VERSION 5.8 ;
BUSBITCHARS "[]" ;
DIVIDERCHAR "/" ;
UNITS
    DATABASE MICRONS 2000 ;
END UNITS

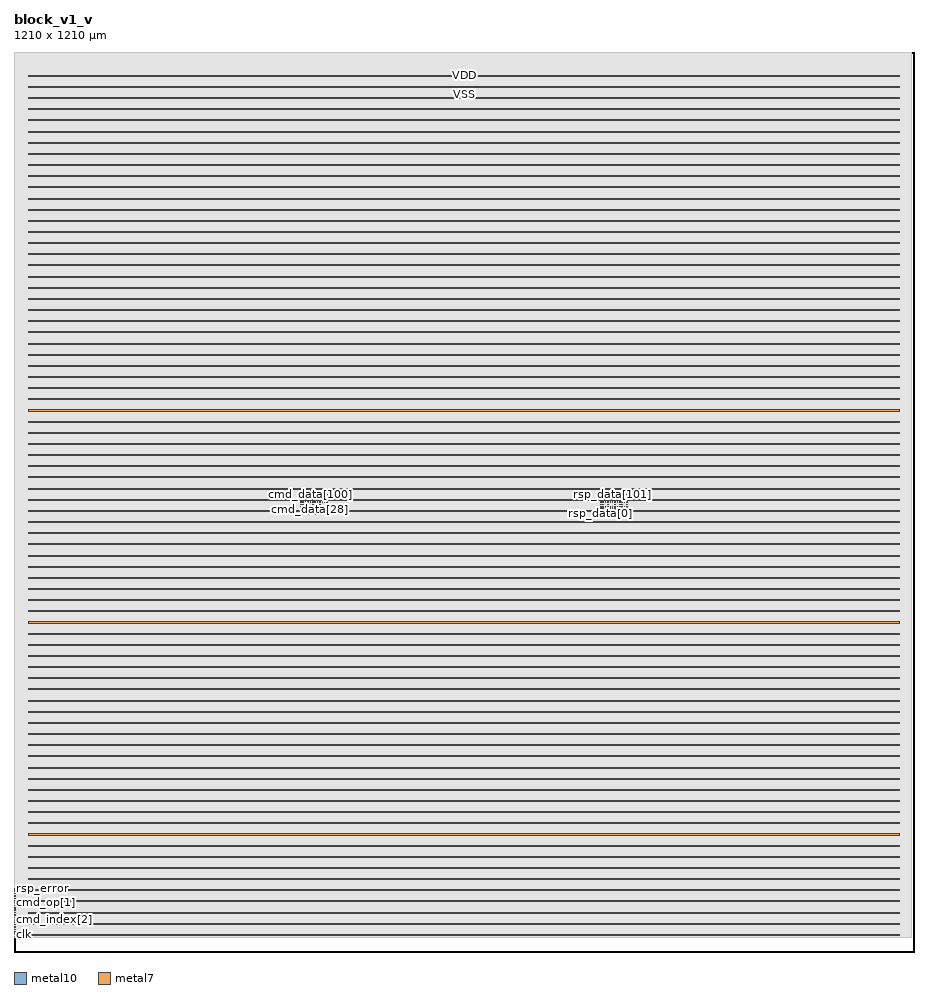
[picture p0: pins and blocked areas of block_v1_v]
MACRO block_v1_v
  FOREIGN block_v1_v 0 0 ;
  CLASS BLOCK ;
  SIZE 1210 BY 1210 ;
  PIN busy
    DIRECTION OUTPUT ;
    USE SIGNAL ;
    PORT
      LAYER metal10 ;
        RECT  1.295 20.47 2.095 21.27 ;
    END
  END busy
  PIN clk
    DIRECTION INPUT ;
    USE SIGNAL ;
    PORT
      LAYER metal10 ;
        RECT  1.295 23.67 2.095 24.47 ;
    END
  END clk
  PIN cmd_data[0]
    DIRECTION INPUT ;
    USE SIGNAL ;
    PORT
      LAYER metal10 ;
        RECT  385.295 588.47 386.095 589.27 ;
    END
  END cmd_data[0]
  PIN cmd_data[100]
    DIRECTION INPUT ;
    USE SIGNAL ;
    PORT
      LAYER metal10 ;
        RECT  398.095 614.07 398.895 614.87 ;
    END
  END cmd_data[100]
  PIN cmd_data[101]
    DIRECTION INPUT ;
    USE SIGNAL ;
    PORT
      LAYER metal10 ;
        RECT  401.295 614.07 402.095 614.87 ;
    END
  END cmd_data[101]
  PIN cmd_data[102]
    DIRECTION INPUT ;
    USE SIGNAL ;
    PORT
      LAYER metal10 ;
        RECT  404.495 614.07 405.295 614.87 ;
    END
  END cmd_data[102]
  PIN cmd_data[103]
    DIRECTION INPUT ;
    USE SIGNAL ;
    PORT
      LAYER metal10 ;
        RECT  407.695 614.07 408.495 614.87 ;
    END
  END cmd_data[103]
  PIN cmd_data[104]
    DIRECTION INPUT ;
    USE SIGNAL ;
    PORT
      LAYER metal10 ;
        RECT  410.895 614.07 411.695 614.87 ;
    END
  END cmd_data[104]
  PIN cmd_data[105]
    DIRECTION INPUT ;
    USE SIGNAL ;
    PORT
      LAYER metal10 ;
        RECT  414.095 614.07 414.895 614.87 ;
    END
  END cmd_data[105]
  PIN cmd_data[106]
    DIRECTION INPUT ;
    USE SIGNAL ;
    PORT
      LAYER metal10 ;
        RECT  417.295 614.07 418.095 614.87 ;
    END
  END cmd_data[106]
  PIN cmd_data[107]
    DIRECTION INPUT ;
    USE SIGNAL ;
    PORT
      LAYER metal10 ;
        RECT  420.495 614.07 421.295 614.87 ;
    END
  END cmd_data[107]
  PIN cmd_data[108]
    DIRECTION INPUT ;
    USE SIGNAL ;
    PORT
      LAYER metal10 ;
        RECT  385.295 617.27 386.095 618.07 ;
    END
  END cmd_data[108]
  PIN cmd_data[109]
    DIRECTION INPUT ;
    USE SIGNAL ;
    PORT
      LAYER metal10 ;
        RECT  388.495 617.27 389.295 618.07 ;
    END
  END cmd_data[109]
  PIN cmd_data[10]
    DIRECTION INPUT ;
    USE SIGNAL ;
    PORT
      LAYER metal10 ;
        RECT  417.295 588.47 418.095 589.27 ;
    END
  END cmd_data[10]
  PIN cmd_data[110]
    DIRECTION INPUT ;
    USE SIGNAL ;
    PORT
      LAYER metal10 ;
        RECT  391.695 617.27 392.495 618.07 ;
    END
  END cmd_data[110]
  PIN cmd_data[111]
    DIRECTION INPUT ;
    USE SIGNAL ;
    PORT
      LAYER metal10 ;
        RECT  394.895 617.27 395.695 618.07 ;
    END
  END cmd_data[111]
  PIN cmd_data[112]
    DIRECTION INPUT ;
    USE SIGNAL ;
    PORT
      LAYER metal10 ;
        RECT  398.095 617.27 398.895 618.07 ;
    END
  END cmd_data[112]
  PIN cmd_data[113]
    DIRECTION INPUT ;
    USE SIGNAL ;
    PORT
      LAYER metal10 ;
        RECT  401.295 617.27 402.095 618.07 ;
    END
  END cmd_data[113]
  PIN cmd_data[114]
    DIRECTION INPUT ;
    USE SIGNAL ;
    PORT
      LAYER metal10 ;
        RECT  404.495 617.27 405.295 618.07 ;
    END
  END cmd_data[114]
  PIN cmd_data[115]
    DIRECTION INPUT ;
    USE SIGNAL ;
    PORT
      LAYER metal10 ;
        RECT  407.695 617.27 408.495 618.07 ;
    END
  END cmd_data[115]
  PIN cmd_data[116]
    DIRECTION INPUT ;
    USE SIGNAL ;
    PORT
      LAYER metal10 ;
        RECT  410.895 617.27 411.695 618.07 ;
    END
  END cmd_data[116]
  PIN cmd_data[117]
    DIRECTION INPUT ;
    USE SIGNAL ;
    PORT
      LAYER metal10 ;
        RECT  414.095 617.27 414.895 618.07 ;
    END
  END cmd_data[117]
  PIN cmd_data[118]
    DIRECTION INPUT ;
    USE SIGNAL ;
    PORT
      LAYER metal10 ;
        RECT  417.295 617.27 418.095 618.07 ;
    END
  END cmd_data[118]
  PIN cmd_data[119]
    DIRECTION INPUT ;
    USE SIGNAL ;
    PORT
      LAYER metal10 ;
        RECT  420.495 617.27 421.295 618.07 ;
    END
  END cmd_data[119]
  PIN cmd_data[11]
    DIRECTION INPUT ;
    USE SIGNAL ;
    PORT
      LAYER metal10 ;
        RECT  420.495 588.47 421.295 589.27 ;
    END
  END cmd_data[11]
  PIN cmd_data[120]
    DIRECTION INPUT ;
    USE SIGNAL ;
    PORT
      LAYER metal10 ;
        RECT  385.295 620.47 386.095 621.27 ;
    END
  END cmd_data[120]
  PIN cmd_data[121]
    DIRECTION INPUT ;
    USE SIGNAL ;
    PORT
      LAYER metal10 ;
        RECT  388.495 620.47 389.295 621.27 ;
    END
  END cmd_data[121]
  PIN cmd_data[122]
    DIRECTION INPUT ;
    USE SIGNAL ;
    PORT
      LAYER metal10 ;
        RECT  391.695 620.47 392.495 621.27 ;
    END
  END cmd_data[122]
  PIN cmd_data[123]
    DIRECTION INPUT ;
    USE SIGNAL ;
    PORT
      LAYER metal10 ;
        RECT  394.895 620.47 395.695 621.27 ;
    END
  END cmd_data[123]
  PIN cmd_data[124]
    DIRECTION INPUT ;
    USE SIGNAL ;
    PORT
      LAYER metal10 ;
        RECT  398.095 620.47 398.895 621.27 ;
    END
  END cmd_data[124]
  PIN cmd_data[125]
    DIRECTION INPUT ;
    USE SIGNAL ;
    PORT
      LAYER metal10 ;
        RECT  401.295 620.47 402.095 621.27 ;
    END
  END cmd_data[125]
  PIN cmd_data[126]
    DIRECTION INPUT ;
    USE SIGNAL ;
    PORT
      LAYER metal10 ;
        RECT  404.495 620.47 405.295 621.27 ;
    END
  END cmd_data[126]
  PIN cmd_data[127]
    DIRECTION INPUT ;
    USE SIGNAL ;
    PORT
      LAYER metal10 ;
        RECT  407.695 620.47 408.495 621.27 ;
    END
  END cmd_data[127]
  PIN cmd_data[12]
    DIRECTION INPUT ;
    USE SIGNAL ;
    PORT
      LAYER metal10 ;
        RECT  385.295 591.67 386.095 592.47 ;
    END
  END cmd_data[12]
  PIN cmd_data[13]
    DIRECTION INPUT ;
    USE SIGNAL ;
    PORT
      LAYER metal10 ;
        RECT  388.495 591.67 389.295 592.47 ;
    END
  END cmd_data[13]
  PIN cmd_data[14]
    DIRECTION INPUT ;
    USE SIGNAL ;
    PORT
      LAYER metal10 ;
        RECT  391.695 591.67 392.495 592.47 ;
    END
  END cmd_data[14]
  PIN cmd_data[15]
    DIRECTION INPUT ;
    USE SIGNAL ;
    PORT
      LAYER metal10 ;
        RECT  394.895 591.67 395.695 592.47 ;
    END
  END cmd_data[15]
  PIN cmd_data[16]
    DIRECTION INPUT ;
    USE SIGNAL ;
    PORT
      LAYER metal10 ;
        RECT  398.095 591.67 398.895 592.47 ;
    END
  END cmd_data[16]
  PIN cmd_data[17]
    DIRECTION INPUT ;
    USE SIGNAL ;
    PORT
      LAYER metal10 ;
        RECT  401.295 591.67 402.095 592.47 ;
    END
  END cmd_data[17]
  PIN cmd_data[18]
    DIRECTION INPUT ;
    USE SIGNAL ;
    PORT
      LAYER metal10 ;
        RECT  404.495 591.67 405.295 592.47 ;
    END
  END cmd_data[18]
  PIN cmd_data[19]
    DIRECTION INPUT ;
    USE SIGNAL ;
    PORT
      LAYER metal10 ;
        RECT  407.695 591.67 408.495 592.47 ;
    END
  END cmd_data[19]
  PIN cmd_data[1]
    DIRECTION INPUT ;
    USE SIGNAL ;
    PORT
      LAYER metal10 ;
        RECT  388.495 588.47 389.295 589.27 ;
    END
  END cmd_data[1]
  PIN cmd_data[20]
    DIRECTION INPUT ;
    USE SIGNAL ;
    PORT
      LAYER metal10 ;
        RECT  410.895 591.67 411.695 592.47 ;
    END
  END cmd_data[20]
  PIN cmd_data[21]
    DIRECTION INPUT ;
    USE SIGNAL ;
    PORT
      LAYER metal10 ;
        RECT  414.095 591.67 414.895 592.47 ;
    END
  END cmd_data[21]
  PIN cmd_data[22]
    DIRECTION INPUT ;
    USE SIGNAL ;
    PORT
      LAYER metal10 ;
        RECT  417.295 591.67 418.095 592.47 ;
    END
  END cmd_data[22]
  PIN cmd_data[23]
    DIRECTION INPUT ;
    USE SIGNAL ;
    PORT
      LAYER metal10 ;
        RECT  420.495 591.67 421.295 592.47 ;
    END
  END cmd_data[23]
  PIN cmd_data[24]
    DIRECTION INPUT ;
    USE SIGNAL ;
    PORT
      LAYER metal10 ;
        RECT  385.295 594.87 386.095 595.67 ;
    END
  END cmd_data[24]
  PIN cmd_data[25]
    DIRECTION INPUT ;
    USE SIGNAL ;
    PORT
      LAYER metal10 ;
        RECT  388.495 594.87 389.295 595.67 ;
    END
  END cmd_data[25]
  PIN cmd_data[26]
    DIRECTION INPUT ;
    USE SIGNAL ;
    PORT
      LAYER metal10 ;
        RECT  391.695 594.87 392.495 595.67 ;
    END
  END cmd_data[26]
  PIN cmd_data[27]
    DIRECTION INPUT ;
    USE SIGNAL ;
    PORT
      LAYER metal10 ;
        RECT  394.895 594.87 395.695 595.67 ;
    END
  END cmd_data[27]
  PIN cmd_data[28]
    DIRECTION INPUT ;
    USE SIGNAL ;
    PORT
      LAYER metal10 ;
        RECT  398.095 594.87 398.895 595.67 ;
    END
  END cmd_data[28]
  PIN cmd_data[29]
    DIRECTION INPUT ;
    USE SIGNAL ;
    PORT
      LAYER metal10 ;
        RECT  401.295 594.87 402.095 595.67 ;
    END
  END cmd_data[29]
  PIN cmd_data[2]
    DIRECTION INPUT ;
    USE SIGNAL ;
    PORT
      LAYER metal10 ;
        RECT  391.695 588.47 392.495 589.27 ;
    END
  END cmd_data[2]
  PIN cmd_data[30]
    DIRECTION INPUT ;
    USE SIGNAL ;
    PORT
      LAYER metal10 ;
        RECT  404.495 594.87 405.295 595.67 ;
    END
  END cmd_data[30]
  PIN cmd_data[31]
    DIRECTION INPUT ;
    USE SIGNAL ;
    PORT
      LAYER metal10 ;
        RECT  407.695 594.87 408.495 595.67 ;
    END
  END cmd_data[31]
  PIN cmd_data[32]
    DIRECTION INPUT ;
    USE SIGNAL ;
    PORT
      LAYER metal10 ;
        RECT  410.895 594.87 411.695 595.67 ;
    END
  END cmd_data[32]
  PIN cmd_data[33]
    DIRECTION INPUT ;
    USE SIGNAL ;
    PORT
      LAYER metal10 ;
        RECT  414.095 594.87 414.895 595.67 ;
    END
  END cmd_data[33]
  PIN cmd_data[34]
    DIRECTION INPUT ;
    USE SIGNAL ;
    PORT
      LAYER metal10 ;
        RECT  417.295 594.87 418.095 595.67 ;
    END
  END cmd_data[34]
  PIN cmd_data[35]
    DIRECTION INPUT ;
    USE SIGNAL ;
    PORT
      LAYER metal10 ;
        RECT  420.495 594.87 421.295 595.67 ;
    END
  END cmd_data[35]
  PIN cmd_data[36]
    DIRECTION INPUT ;
    USE SIGNAL ;
    PORT
      LAYER metal10 ;
        RECT  385.295 598.07 386.095 598.87 ;
    END
  END cmd_data[36]
  PIN cmd_data[37]
    DIRECTION INPUT ;
    USE SIGNAL ;
    PORT
      LAYER metal10 ;
        RECT  388.495 598.07 389.295 598.87 ;
    END
  END cmd_data[37]
  PIN cmd_data[38]
    DIRECTION INPUT ;
    USE SIGNAL ;
    PORT
      LAYER metal10 ;
        RECT  391.695 598.07 392.495 598.87 ;
    END
  END cmd_data[38]
  PIN cmd_data[39]
    DIRECTION INPUT ;
    USE SIGNAL ;
    PORT
      LAYER metal10 ;
        RECT  394.895 598.07 395.695 598.87 ;
    END
  END cmd_data[39]
  PIN cmd_data[3]
    DIRECTION INPUT ;
    USE SIGNAL ;
    PORT
      LAYER metal10 ;
        RECT  394.895 588.47 395.695 589.27 ;
    END
  END cmd_data[3]
  PIN cmd_data[40]
    DIRECTION INPUT ;
    USE SIGNAL ;
    PORT
      LAYER metal10 ;
        RECT  398.095 598.07 398.895 598.87 ;
    END
  END cmd_data[40]
  PIN cmd_data[41]
    DIRECTION INPUT ;
    USE SIGNAL ;
    PORT
      LAYER metal10 ;
        RECT  401.295 598.07 402.095 598.87 ;
    END
  END cmd_data[41]
  PIN cmd_data[42]
    DIRECTION INPUT ;
    USE SIGNAL ;
    PORT
      LAYER metal10 ;
        RECT  404.495 598.07 405.295 598.87 ;
    END
  END cmd_data[42]
  PIN cmd_data[43]
    DIRECTION INPUT ;
    USE SIGNAL ;
    PORT
      LAYER metal10 ;
        RECT  407.695 598.07 408.495 598.87 ;
    END
  END cmd_data[43]
  PIN cmd_data[44]
    DIRECTION INPUT ;
    USE SIGNAL ;
    PORT
      LAYER metal10 ;
        RECT  410.895 598.07 411.695 598.87 ;
    END
  END cmd_data[44]
  PIN cmd_data[45]
    DIRECTION INPUT ;
    USE SIGNAL ;
    PORT
      LAYER metal10 ;
        RECT  414.095 598.07 414.895 598.87 ;
    END
  END cmd_data[45]
  PIN cmd_data[46]
    DIRECTION INPUT ;
    USE SIGNAL ;
    PORT
      LAYER metal10 ;
        RECT  417.295 598.07 418.095 598.87 ;
    END
  END cmd_data[46]
  PIN cmd_data[47]
    DIRECTION INPUT ;
    USE SIGNAL ;
    PORT
      LAYER metal10 ;
        RECT  420.495 598.07 421.295 598.87 ;
    END
  END cmd_data[47]
  PIN cmd_data[48]
    DIRECTION INPUT ;
    USE SIGNAL ;
    PORT
      LAYER metal10 ;
        RECT  385.295 601.27 386.095 602.07 ;
    END
  END cmd_data[48]
  PIN cmd_data[49]
    DIRECTION INPUT ;
    USE SIGNAL ;
    PORT
      LAYER metal10 ;
        RECT  388.495 601.27 389.295 602.07 ;
    END
  END cmd_data[49]
  PIN cmd_data[4]
    DIRECTION INPUT ;
    USE SIGNAL ;
    PORT
      LAYER metal10 ;
        RECT  398.095 588.47 398.895 589.27 ;
    END
  END cmd_data[4]
  PIN cmd_data[50]
    DIRECTION INPUT ;
    USE SIGNAL ;
    PORT
      LAYER metal10 ;
        RECT  391.695 601.27 392.495 602.07 ;
    END
  END cmd_data[50]
  PIN cmd_data[51]
    DIRECTION INPUT ;
    USE SIGNAL ;
    PORT
      LAYER metal10 ;
        RECT  394.895 601.27 395.695 602.07 ;
    END
  END cmd_data[51]
  PIN cmd_data[52]
    DIRECTION INPUT ;
    USE SIGNAL ;
    PORT
      LAYER metal10 ;
        RECT  398.095 601.27 398.895 602.07 ;
    END
  END cmd_data[52]
  PIN cmd_data[53]
    DIRECTION INPUT ;
    USE SIGNAL ;
    PORT
      LAYER metal10 ;
        RECT  401.295 601.27 402.095 602.07 ;
    END
  END cmd_data[53]
  PIN cmd_data[54]
    DIRECTION INPUT ;
    USE SIGNAL ;
    PORT
      LAYER metal10 ;
        RECT  404.495 601.27 405.295 602.07 ;
    END
  END cmd_data[54]
  PIN cmd_data[55]
    DIRECTION INPUT ;
    USE SIGNAL ;
    PORT
      LAYER metal10 ;
        RECT  407.695 601.27 408.495 602.07 ;
    END
  END cmd_data[55]
  PIN cmd_data[56]
    DIRECTION INPUT ;
    USE SIGNAL ;
    PORT
      LAYER metal10 ;
        RECT  410.895 601.27 411.695 602.07 ;
    END
  END cmd_data[56]
  PIN cmd_data[57]
    DIRECTION INPUT ;
    USE SIGNAL ;
    PORT
      LAYER metal10 ;
        RECT  414.095 601.27 414.895 602.07 ;
    END
  END cmd_data[57]
  PIN cmd_data[58]
    DIRECTION INPUT ;
    USE SIGNAL ;
    PORT
      LAYER metal10 ;
        RECT  417.295 601.27 418.095 602.07 ;
    END
  END cmd_data[58]
  PIN cmd_data[59]
    DIRECTION INPUT ;
    USE SIGNAL ;
    PORT
      LAYER metal10 ;
        RECT  420.495 601.27 421.295 602.07 ;
    END
  END cmd_data[59]
  PIN cmd_data[5]
    DIRECTION INPUT ;
    USE SIGNAL ;
    PORT
      LAYER metal10 ;
        RECT  401.295 588.47 402.095 589.27 ;
    END
  END cmd_data[5]
  PIN cmd_data[60]
    DIRECTION INPUT ;
    USE SIGNAL ;
    PORT
      LAYER metal10 ;
        RECT  385.295 604.47 386.095 605.27 ;
    END
  END cmd_data[60]
  PIN cmd_data[61]
    DIRECTION INPUT ;
    USE SIGNAL ;
    PORT
      LAYER metal10 ;
        RECT  388.495 604.47 389.295 605.27 ;
    END
  END cmd_data[61]
  PIN cmd_data[62]
    DIRECTION INPUT ;
    USE SIGNAL ;
    PORT
      LAYER metal10 ;
        RECT  391.695 604.47 392.495 605.27 ;
    END
  END cmd_data[62]
  PIN cmd_data[63]
    DIRECTION INPUT ;
    USE SIGNAL ;
    PORT
      LAYER metal10 ;
        RECT  394.895 604.47 395.695 605.27 ;
    END
  END cmd_data[63]
  PIN cmd_data[64]
    DIRECTION INPUT ;
    USE SIGNAL ;
    PORT
      LAYER metal10 ;
        RECT  398.095 604.47 398.895 605.27 ;
    END
  END cmd_data[64]
  PIN cmd_data[65]
    DIRECTION INPUT ;
    USE SIGNAL ;
    PORT
      LAYER metal10 ;
        RECT  401.295 604.47 402.095 605.27 ;
    END
  END cmd_data[65]
  PIN cmd_data[66]
    DIRECTION INPUT ;
    USE SIGNAL ;
    PORT
      LAYER metal10 ;
        RECT  404.495 604.47 405.295 605.27 ;
    END
  END cmd_data[66]
  PIN cmd_data[67]
    DIRECTION INPUT ;
    USE SIGNAL ;
    PORT
      LAYER metal10 ;
        RECT  407.695 604.47 408.495 605.27 ;
    END
  END cmd_data[67]
  PIN cmd_data[68]
    DIRECTION INPUT ;
    USE SIGNAL ;
    PORT
      LAYER metal10 ;
        RECT  410.895 604.47 411.695 605.27 ;
    END
  END cmd_data[68]
  PIN cmd_data[69]
    DIRECTION INPUT ;
    USE SIGNAL ;
    PORT
      LAYER metal10 ;
        RECT  414.095 604.47 414.895 605.27 ;
    END
  END cmd_data[69]
  PIN cmd_data[6]
    DIRECTION INPUT ;
    USE SIGNAL ;
    PORT
      LAYER metal10 ;
        RECT  404.495 588.47 405.295 589.27 ;
    END
  END cmd_data[6]
  PIN cmd_data[70]
    DIRECTION INPUT ;
    USE SIGNAL ;
    PORT
      LAYER metal10 ;
        RECT  417.295 604.47 418.095 605.27 ;
    END
  END cmd_data[70]
  PIN cmd_data[71]
    DIRECTION INPUT ;
    USE SIGNAL ;
    PORT
      LAYER metal10 ;
        RECT  420.495 604.47 421.295 605.27 ;
    END
  END cmd_data[71]
  PIN cmd_data[72]
    DIRECTION INPUT ;
    USE SIGNAL ;
    PORT
      LAYER metal10 ;
        RECT  385.295 607.67 386.095 608.47 ;
    END
  END cmd_data[72]
  PIN cmd_data[73]
    DIRECTION INPUT ;
    USE SIGNAL ;
    PORT
      LAYER metal10 ;
        RECT  388.495 607.67 389.295 608.47 ;
    END
  END cmd_data[73]
  PIN cmd_data[74]
    DIRECTION INPUT ;
    USE SIGNAL ;
    PORT
      LAYER metal10 ;
        RECT  391.695 607.67 392.495 608.47 ;
    END
  END cmd_data[74]
  PIN cmd_data[75]
    DIRECTION INPUT ;
    USE SIGNAL ;
    PORT
      LAYER metal10 ;
        RECT  394.895 607.67 395.695 608.47 ;
    END
  END cmd_data[75]
  PIN cmd_data[76]
    DIRECTION INPUT ;
    USE SIGNAL ;
    PORT
      LAYER metal10 ;
        RECT  398.095 607.67 398.895 608.47 ;
    END
  END cmd_data[76]
  PIN cmd_data[77]
    DIRECTION INPUT ;
    USE SIGNAL ;
    PORT
      LAYER metal10 ;
        RECT  401.295 607.67 402.095 608.47 ;
    END
  END cmd_data[77]
  PIN cmd_data[78]
    DIRECTION INPUT ;
    USE SIGNAL ;
    PORT
      LAYER metal10 ;
        RECT  404.495 607.67 405.295 608.47 ;
    END
  END cmd_data[78]
  PIN cmd_data[79]
    DIRECTION INPUT ;
    USE SIGNAL ;
    PORT
      LAYER metal10 ;
        RECT  407.695 607.67 408.495 608.47 ;
    END
  END cmd_data[79]
  PIN cmd_data[7]
    DIRECTION INPUT ;
    USE SIGNAL ;
    PORT
      LAYER metal10 ;
        RECT  407.695 588.47 408.495 589.27 ;
    END
  END cmd_data[7]
  PIN cmd_data[80]
    DIRECTION INPUT ;
    USE SIGNAL ;
    PORT
      LAYER metal10 ;
        RECT  410.895 607.67 411.695 608.47 ;
    END
  END cmd_data[80]
  PIN cmd_data[81]
    DIRECTION INPUT ;
    USE SIGNAL ;
    PORT
      LAYER metal10 ;
        RECT  414.095 607.67 414.895 608.47 ;
    END
  END cmd_data[81]
  PIN cmd_data[82]
    DIRECTION INPUT ;
    USE SIGNAL ;
    PORT
      LAYER metal10 ;
        RECT  417.295 607.67 418.095 608.47 ;
    END
  END cmd_data[82]
  PIN cmd_data[83]
    DIRECTION INPUT ;
    USE SIGNAL ;
    PORT
      LAYER metal10 ;
        RECT  420.495 607.67 421.295 608.47 ;
    END
  END cmd_data[83]
  PIN cmd_data[84]
    DIRECTION INPUT ;
    USE SIGNAL ;
    PORT
      LAYER metal10 ;
        RECT  385.295 610.87 386.095 611.67 ;
    END
  END cmd_data[84]
  PIN cmd_data[85]
    DIRECTION INPUT ;
    USE SIGNAL ;
    PORT
      LAYER metal10 ;
        RECT  388.495 610.87 389.295 611.67 ;
    END
  END cmd_data[85]
  PIN cmd_data[86]
    DIRECTION INPUT ;
    USE SIGNAL ;
    PORT
      LAYER metal10 ;
        RECT  391.695 610.87 392.495 611.67 ;
    END
  END cmd_data[86]
  PIN cmd_data[87]
    DIRECTION INPUT ;
    USE SIGNAL ;
    PORT
      LAYER metal10 ;
        RECT  394.895 610.87 395.695 611.67 ;
    END
  END cmd_data[87]
  PIN cmd_data[88]
    DIRECTION INPUT ;
    USE SIGNAL ;
    PORT
      LAYER metal10 ;
        RECT  398.095 610.87 398.895 611.67 ;
    END
  END cmd_data[88]
  PIN cmd_data[89]
    DIRECTION INPUT ;
    USE SIGNAL ;
    PORT
      LAYER metal10 ;
        RECT  401.295 610.87 402.095 611.67 ;
    END
  END cmd_data[89]
  PIN cmd_data[8]
    DIRECTION INPUT ;
    USE SIGNAL ;
    PORT
      LAYER metal10 ;
        RECT  410.895 588.47 411.695 589.27 ;
    END
  END cmd_data[8]
  PIN cmd_data[90]
    DIRECTION INPUT ;
    USE SIGNAL ;
    PORT
      LAYER metal10 ;
        RECT  404.495 610.87 405.295 611.67 ;
    END
  END cmd_data[90]
  PIN cmd_data[91]
    DIRECTION INPUT ;
    USE SIGNAL ;
    PORT
      LAYER metal10 ;
        RECT  407.695 610.87 408.495 611.67 ;
    END
  END cmd_data[91]
  PIN cmd_data[92]
    DIRECTION INPUT ;
    USE SIGNAL ;
    PORT
      LAYER metal10 ;
        RECT  410.895 610.87 411.695 611.67 ;
    END
  END cmd_data[92]
  PIN cmd_data[93]
    DIRECTION INPUT ;
    USE SIGNAL ;
    PORT
      LAYER metal10 ;
        RECT  414.095 610.87 414.895 611.67 ;
    END
  END cmd_data[93]
  PIN cmd_data[94]
    DIRECTION INPUT ;
    USE SIGNAL ;
    PORT
      LAYER metal10 ;
        RECT  417.295 610.87 418.095 611.67 ;
    END
  END cmd_data[94]
  PIN cmd_data[95]
    DIRECTION INPUT ;
    USE SIGNAL ;
    PORT
      LAYER metal10 ;
        RECT  420.495 610.87 421.295 611.67 ;
    END
  END cmd_data[95]
  PIN cmd_data[96]
    DIRECTION INPUT ;
    USE SIGNAL ;
    PORT
      LAYER metal10 ;
        RECT  385.295 614.07 386.095 614.87 ;
    END
  END cmd_data[96]
  PIN cmd_data[97]
    DIRECTION INPUT ;
    USE SIGNAL ;
    PORT
      LAYER metal10 ;
        RECT  388.495 614.07 389.295 614.87 ;
    END
  END cmd_data[97]
  PIN cmd_data[98]
    DIRECTION INPUT ;
    USE SIGNAL ;
    PORT
      LAYER metal10 ;
        RECT  391.695 614.07 392.495 614.87 ;
    END
  END cmd_data[98]
  PIN cmd_data[99]
    DIRECTION INPUT ;
    USE SIGNAL ;
    PORT
      LAYER metal10 ;
        RECT  394.895 614.07 395.695 614.87 ;
    END
  END cmd_data[99]
  PIN cmd_data[9]
    DIRECTION INPUT ;
    USE SIGNAL ;
    PORT
      LAYER metal10 ;
        RECT  414.095 588.47 414.895 589.27 ;
    END
  END cmd_data[9]
  PIN cmd_index[0]
    DIRECTION INPUT ;
    USE SIGNAL ;
    PORT
      LAYER metal10 ;
        RECT  1.295 26.87 2.095 27.67 ;
    END
  END cmd_index[0]
  PIN cmd_index[1]
    DIRECTION INPUT ;
    USE SIGNAL ;
    PORT
      LAYER metal10 ;
        RECT  1.295 30.07 2.095 30.87 ;
    END
  END cmd_index[1]
  PIN cmd_index[2]
    DIRECTION INPUT ;
    USE SIGNAL ;
    PORT
      LAYER metal10 ;
        RECT  1.295 33.27 2.095 34.07 ;
    END
  END cmd_index[2]
  PIN cmd_index[3]
    DIRECTION INPUT ;
    USE SIGNAL ;
    PORT
      LAYER metal10 ;
        RECT  1.295 36.47 2.095 37.27 ;
    END
  END cmd_index[3]
  PIN cmd_index[4]
    DIRECTION INPUT ;
    USE SIGNAL ;
    PORT
      LAYER metal10 ;
        RECT  1.295 39.67 2.095 40.47 ;
    END
  END cmd_index[4]
  PIN cmd_index[5]
    DIRECTION INPUT ;
    USE SIGNAL ;
    PORT
      LAYER metal10 ;
        RECT  1.295 42.87 2.095 43.67 ;
    END
  END cmd_index[5]
  PIN cmd_index[6]
    DIRECTION INPUT ;
    USE SIGNAL ;
    PORT
      LAYER metal10 ;
        RECT  1.295 46.07 2.095 46.87 ;
    END
  END cmd_index[6]
  PIN cmd_index[7]
    DIRECTION INPUT ;
    USE SIGNAL ;
    PORT
      LAYER metal10 ;
        RECT  1.295 49.27 2.095 50.07 ;
    END
  END cmd_index[7]
  PIN cmd_op[0]
    DIRECTION INPUT ;
    USE SIGNAL ;
    PORT
      LAYER metal10 ;
        RECT  1.295 52.47 2.095 53.27 ;
    END
  END cmd_op[0]
  PIN cmd_op[1]
    DIRECTION INPUT ;
    USE SIGNAL ;
    PORT
      LAYER metal10 ;
        RECT  1.295 55.67 2.095 56.47 ;
    END
  END cmd_op[1]
  PIN cmd_op[2]
    DIRECTION INPUT ;
    USE SIGNAL ;
    PORT
      LAYER metal10 ;
        RECT  1.295 58.87 2.095 59.67 ;
    END
  END cmd_op[2]
  PIN cmd_op[3]
    DIRECTION INPUT ;
    USE SIGNAL ;
    PORT
      LAYER metal10 ;
        RECT  1.295 62.07 2.095 62.87 ;
    END
  END cmd_op[3]
  PIN cmd_ready
    DIRECTION OUTPUT ;
    USE SIGNAL ;
    PORT
      LAYER metal10 ;
        RECT  1.295 65.27 2.095 66.07 ;
    END
  END cmd_ready
  PIN cmd_valid
    DIRECTION INPUT ;
    USE SIGNAL ;
    PORT
      LAYER metal10 ;
        RECT  1.295 68.47 2.095 69.27 ;
    END
  END cmd_valid
  PIN reset
    DIRECTION INPUT ;
    USE SIGNAL ;
    PORT
      LAYER metal10 ;
        RECT  1.295 71.67 2.095 72.47 ;
    END
  END reset
  PIN rsp_data[0]
    DIRECTION OUTPUT ;
    USE SIGNAL ;
    PORT
      LAYER metal10 ;
        RECT  788.495 588.47 789.295 589.27 ;
    END
  END rsp_data[0]
  PIN rsp_data[100]
    DIRECTION OUTPUT ;
    USE SIGNAL ;
    PORT
      LAYER metal10 ;
        RECT  801.295 614.07 802.095 614.87 ;
    END
  END rsp_data[100]
  PIN rsp_data[101]
    DIRECTION OUTPUT ;
    USE SIGNAL ;
    PORT
      LAYER metal10 ;
        RECT  804.495 614.07 805.295 614.87 ;
    END
  END rsp_data[101]
  PIN rsp_data[102]
    DIRECTION OUTPUT ;
    USE SIGNAL ;
    PORT
      LAYER metal10 ;
        RECT  807.695 614.07 808.495 614.87 ;
    END
  END rsp_data[102]
  PIN rsp_data[103]
    DIRECTION OUTPUT ;
    USE SIGNAL ;
    PORT
      LAYER metal10 ;
        RECT  810.895 614.07 811.695 614.87 ;
    END
  END rsp_data[103]
  PIN rsp_data[104]
    DIRECTION OUTPUT ;
    USE SIGNAL ;
    PORT
      LAYER metal10 ;
        RECT  814.095 614.07 814.895 614.87 ;
    END
  END rsp_data[104]
  PIN rsp_data[105]
    DIRECTION OUTPUT ;
    USE SIGNAL ;
    PORT
      LAYER metal10 ;
        RECT  817.295 614.07 818.095 614.87 ;
    END
  END rsp_data[105]
  PIN rsp_data[106]
    DIRECTION OUTPUT ;
    USE SIGNAL ;
    PORT
      LAYER metal10 ;
        RECT  820.495 614.07 821.295 614.87 ;
    END
  END rsp_data[106]
  PIN rsp_data[107]
    DIRECTION OUTPUT ;
    USE SIGNAL ;
    PORT
      LAYER metal10 ;
        RECT  823.695 614.07 824.495 614.87 ;
    END
  END rsp_data[107]
  PIN rsp_data[108]
    DIRECTION OUTPUT ;
    USE SIGNAL ;
    PORT
      LAYER metal10 ;
        RECT  788.495 617.27 789.295 618.07 ;
    END
  END rsp_data[108]
  PIN rsp_data[109]
    DIRECTION OUTPUT ;
    USE SIGNAL ;
    PORT
      LAYER metal10 ;
        RECT  791.695 617.27 792.495 618.07 ;
    END
  END rsp_data[109]
  PIN rsp_data[10]
    DIRECTION OUTPUT ;
    USE SIGNAL ;
    PORT
      LAYER metal10 ;
        RECT  820.495 588.47 821.295 589.27 ;
    END
  END rsp_data[10]
  PIN rsp_data[110]
    DIRECTION OUTPUT ;
    USE SIGNAL ;
    PORT
      LAYER metal10 ;
        RECT  794.895 617.27 795.695 618.07 ;
    END
  END rsp_data[110]
  PIN rsp_data[111]
    DIRECTION OUTPUT ;
    USE SIGNAL ;
    PORT
      LAYER metal10 ;
        RECT  798.095 617.27 798.895 618.07 ;
    END
  END rsp_data[111]
  PIN rsp_data[112]
    DIRECTION OUTPUT ;
    USE SIGNAL ;
    PORT
      LAYER metal10 ;
        RECT  801.295 617.27 802.095 618.07 ;
    END
  END rsp_data[112]
  PIN rsp_data[113]
    DIRECTION OUTPUT ;
    USE SIGNAL ;
    PORT
      LAYER metal10 ;
        RECT  804.495 617.27 805.295 618.07 ;
    END
  END rsp_data[113]
  PIN rsp_data[114]
    DIRECTION OUTPUT ;
    USE SIGNAL ;
    PORT
      LAYER metal10 ;
        RECT  807.695 617.27 808.495 618.07 ;
    END
  END rsp_data[114]
  PIN rsp_data[115]
    DIRECTION OUTPUT ;
    USE SIGNAL ;
    PORT
      LAYER metal10 ;
        RECT  810.895 617.27 811.695 618.07 ;
    END
  END rsp_data[115]
  PIN rsp_data[116]
    DIRECTION OUTPUT ;
    USE SIGNAL ;
    PORT
      LAYER metal10 ;
        RECT  814.095 617.27 814.895 618.07 ;
    END
  END rsp_data[116]
  PIN rsp_data[117]
    DIRECTION OUTPUT ;
    USE SIGNAL ;
    PORT
      LAYER metal10 ;
        RECT  817.295 617.27 818.095 618.07 ;
    END
  END rsp_data[117]
  PIN rsp_data[118]
    DIRECTION OUTPUT ;
    USE SIGNAL ;
    PORT
      LAYER metal10 ;
        RECT  820.495 617.27 821.295 618.07 ;
    END
  END rsp_data[118]
  PIN rsp_data[119]
    DIRECTION OUTPUT ;
    USE SIGNAL ;
    PORT
      LAYER metal10 ;
        RECT  823.695 617.27 824.495 618.07 ;
    END
  END rsp_data[119]
  PIN rsp_data[11]
    DIRECTION OUTPUT ;
    USE SIGNAL ;
    PORT
      LAYER metal10 ;
        RECT  823.695 588.47 824.495 589.27 ;
    END
  END rsp_data[11]
  PIN rsp_data[120]
    DIRECTION OUTPUT ;
    USE SIGNAL ;
    PORT
      LAYER metal10 ;
        RECT  788.495 620.47 789.295 621.27 ;
    END
  END rsp_data[120]
  PIN rsp_data[121]
    DIRECTION OUTPUT ;
    USE SIGNAL ;
    PORT
      LAYER metal10 ;
        RECT  791.695 620.47 792.495 621.27 ;
    END
  END rsp_data[121]
  PIN rsp_data[122]
    DIRECTION OUTPUT ;
    USE SIGNAL ;
    PORT
      LAYER metal10 ;
        RECT  794.895 620.47 795.695 621.27 ;
    END
  END rsp_data[122]
  PIN rsp_data[123]
    DIRECTION OUTPUT ;
    USE SIGNAL ;
    PORT
      LAYER metal10 ;
        RECT  798.095 620.47 798.895 621.27 ;
    END
  END rsp_data[123]
  PIN rsp_data[124]
    DIRECTION OUTPUT ;
    USE SIGNAL ;
    PORT
      LAYER metal10 ;
        RECT  801.295 620.47 802.095 621.27 ;
    END
  END rsp_data[124]
  PIN rsp_data[125]
    DIRECTION OUTPUT ;
    USE SIGNAL ;
    PORT
      LAYER metal10 ;
        RECT  804.495 620.47 805.295 621.27 ;
    END
  END rsp_data[125]
  PIN rsp_data[126]
    DIRECTION OUTPUT ;
    USE SIGNAL ;
    PORT
      LAYER metal10 ;
        RECT  807.695 620.47 808.495 621.27 ;
    END
  END rsp_data[126]
  PIN rsp_data[127]
    DIRECTION OUTPUT ;
    USE SIGNAL ;
    PORT
      LAYER metal10 ;
        RECT  810.895 620.47 811.695 621.27 ;
    END
  END rsp_data[127]
  PIN rsp_data[12]
    DIRECTION OUTPUT ;
    USE SIGNAL ;
    PORT
      LAYER metal10 ;
        RECT  788.495 591.67 789.295 592.47 ;
    END
  END rsp_data[12]
  PIN rsp_data[13]
    DIRECTION OUTPUT ;
    USE SIGNAL ;
    PORT
      LAYER metal10 ;
        RECT  791.695 591.67 792.495 592.47 ;
    END
  END rsp_data[13]
  PIN rsp_data[14]
    DIRECTION OUTPUT ;
    USE SIGNAL ;
    PORT
      LAYER metal10 ;
        RECT  794.895 591.67 795.695 592.47 ;
    END
  END rsp_data[14]
  PIN rsp_data[15]
    DIRECTION OUTPUT ;
    USE SIGNAL ;
    PORT
      LAYER metal10 ;
        RECT  798.095 591.67 798.895 592.47 ;
    END
  END rsp_data[15]
  PIN rsp_data[16]
    DIRECTION OUTPUT ;
    USE SIGNAL ;
    PORT
      LAYER metal10 ;
        RECT  801.295 591.67 802.095 592.47 ;
    END
  END rsp_data[16]
  PIN rsp_data[17]
    DIRECTION OUTPUT ;
    USE SIGNAL ;
    PORT
      LAYER metal10 ;
        RECT  804.495 591.67 805.295 592.47 ;
    END
  END rsp_data[17]
  PIN rsp_data[18]
    DIRECTION OUTPUT ;
    USE SIGNAL ;
    PORT
      LAYER metal10 ;
        RECT  807.695 591.67 808.495 592.47 ;
    END
  END rsp_data[18]
  PIN rsp_data[19]
    DIRECTION OUTPUT ;
    USE SIGNAL ;
    PORT
      LAYER metal10 ;
        RECT  810.895 591.67 811.695 592.47 ;
    END
  END rsp_data[19]
  PIN rsp_data[1]
    DIRECTION OUTPUT ;
    USE SIGNAL ;
    PORT
      LAYER metal10 ;
        RECT  791.695 588.47 792.495 589.27 ;
    END
  END rsp_data[1]
  PIN rsp_data[20]
    DIRECTION OUTPUT ;
    USE SIGNAL ;
    PORT
      LAYER metal10 ;
        RECT  814.095 591.67 814.895 592.47 ;
    END
  END rsp_data[20]
  PIN rsp_data[21]
    DIRECTION OUTPUT ;
    USE SIGNAL ;
    PORT
      LAYER metal10 ;
        RECT  817.295 591.67 818.095 592.47 ;
    END
  END rsp_data[21]
  PIN rsp_data[22]
    DIRECTION OUTPUT ;
    USE SIGNAL ;
    PORT
      LAYER metal10 ;
        RECT  820.495 591.67 821.295 592.47 ;
    END
  END rsp_data[22]
  PIN rsp_data[23]
    DIRECTION OUTPUT ;
    USE SIGNAL ;
    PORT
      LAYER metal10 ;
        RECT  823.695 591.67 824.495 592.47 ;
    END
  END rsp_data[23]
  PIN rsp_data[24]
    DIRECTION OUTPUT ;
    USE SIGNAL ;
    PORT
      LAYER metal10 ;
        RECT  788.495 594.87 789.295 595.67 ;
    END
  END rsp_data[24]
  PIN rsp_data[25]
    DIRECTION OUTPUT ;
    USE SIGNAL ;
    PORT
      LAYER metal10 ;
        RECT  791.695 594.87 792.495 595.67 ;
    END
  END rsp_data[25]
  PIN rsp_data[26]
    DIRECTION OUTPUT ;
    USE SIGNAL ;
    PORT
      LAYER metal10 ;
        RECT  794.895 594.87 795.695 595.67 ;
    END
  END rsp_data[26]
  PIN rsp_data[27]
    DIRECTION OUTPUT ;
    USE SIGNAL ;
    PORT
      LAYER metal10 ;
        RECT  798.095 594.87 798.895 595.67 ;
    END
  END rsp_data[27]
  PIN rsp_data[28]
    DIRECTION OUTPUT ;
    USE SIGNAL ;
    PORT
      LAYER metal10 ;
        RECT  801.295 594.87 802.095 595.67 ;
    END
  END rsp_data[28]
  PIN rsp_data[29]
    DIRECTION OUTPUT ;
    USE SIGNAL ;
    PORT
      LAYER metal10 ;
        RECT  804.495 594.87 805.295 595.67 ;
    END
  END rsp_data[29]
  PIN rsp_data[2]
    DIRECTION OUTPUT ;
    USE SIGNAL ;
    PORT
      LAYER metal10 ;
        RECT  794.895 588.47 795.695 589.27 ;
    END
  END rsp_data[2]
  PIN rsp_data[30]
    DIRECTION OUTPUT ;
    USE SIGNAL ;
    PORT
      LAYER metal10 ;
        RECT  807.695 594.87 808.495 595.67 ;
    END
  END rsp_data[30]
  PIN rsp_data[31]
    DIRECTION OUTPUT ;
    USE SIGNAL ;
    PORT
      LAYER metal10 ;
        RECT  810.895 594.87 811.695 595.67 ;
    END
  END rsp_data[31]
  PIN rsp_data[32]
    DIRECTION OUTPUT ;
    USE SIGNAL ;
    PORT
      LAYER metal10 ;
        RECT  814.095 594.87 814.895 595.67 ;
    END
  END rsp_data[32]
  PIN rsp_data[33]
    DIRECTION OUTPUT ;
    USE SIGNAL ;
    PORT
      LAYER metal10 ;
        RECT  817.295 594.87 818.095 595.67 ;
    END
  END rsp_data[33]
  PIN rsp_data[34]
    DIRECTION OUTPUT ;
    USE SIGNAL ;
    PORT
      LAYER metal10 ;
        RECT  820.495 594.87 821.295 595.67 ;
    END
  END rsp_data[34]
  PIN rsp_data[35]
    DIRECTION OUTPUT ;
    USE SIGNAL ;
    PORT
      LAYER metal10 ;
        RECT  823.695 594.87 824.495 595.67 ;
    END
  END rsp_data[35]
  PIN rsp_data[36]
    DIRECTION OUTPUT ;
    USE SIGNAL ;
    PORT
      LAYER metal10 ;
        RECT  788.495 598.07 789.295 598.87 ;
    END
  END rsp_data[36]
  PIN rsp_data[37]
    DIRECTION OUTPUT ;
    USE SIGNAL ;
    PORT
      LAYER metal10 ;
        RECT  791.695 598.07 792.495 598.87 ;
    END
  END rsp_data[37]
  PIN rsp_data[38]
    DIRECTION OUTPUT ;
    USE SIGNAL ;
    PORT
      LAYER metal10 ;
        RECT  794.895 598.07 795.695 598.87 ;
    END
  END rsp_data[38]
  PIN rsp_data[39]
    DIRECTION OUTPUT ;
    USE SIGNAL ;
    PORT
      LAYER metal10 ;
        RECT  798.095 598.07 798.895 598.87 ;
    END
  END rsp_data[39]
  PIN rsp_data[3]
    DIRECTION OUTPUT ;
    USE SIGNAL ;
    PORT
      LAYER metal10 ;
        RECT  798.095 588.47 798.895 589.27 ;
    END
  END rsp_data[3]
  PIN rsp_data[40]
    DIRECTION OUTPUT ;
    USE SIGNAL ;
    PORT
      LAYER metal10 ;
        RECT  801.295 598.07 802.095 598.87 ;
    END
  END rsp_data[40]
  PIN rsp_data[41]
    DIRECTION OUTPUT ;
    USE SIGNAL ;
    PORT
      LAYER metal10 ;
        RECT  804.495 598.07 805.295 598.87 ;
    END
  END rsp_data[41]
  PIN rsp_data[42]
    DIRECTION OUTPUT ;
    USE SIGNAL ;
    PORT
      LAYER metal10 ;
        RECT  807.695 598.07 808.495 598.87 ;
    END
  END rsp_data[42]
  PIN rsp_data[43]
    DIRECTION OUTPUT ;
    USE SIGNAL ;
    PORT
      LAYER metal10 ;
        RECT  810.895 598.07 811.695 598.87 ;
    END
  END rsp_data[43]
  PIN rsp_data[44]
    DIRECTION OUTPUT ;
    USE SIGNAL ;
    PORT
      LAYER metal10 ;
        RECT  814.095 598.07 814.895 598.87 ;
    END
  END rsp_data[44]
  PIN rsp_data[45]
    DIRECTION OUTPUT ;
    USE SIGNAL ;
    PORT
      LAYER metal10 ;
        RECT  817.295 598.07 818.095 598.87 ;
    END
  END rsp_data[45]
  PIN rsp_data[46]
    DIRECTION OUTPUT ;
    USE SIGNAL ;
    PORT
      LAYER metal10 ;
        RECT  820.495 598.07 821.295 598.87 ;
    END
  END rsp_data[46]
  PIN rsp_data[47]
    DIRECTION OUTPUT ;
    USE SIGNAL ;
    PORT
      LAYER metal10 ;
        RECT  823.695 598.07 824.495 598.87 ;
    END
  END rsp_data[47]
  PIN rsp_data[48]
    DIRECTION OUTPUT ;
    USE SIGNAL ;
    PORT
      LAYER metal10 ;
        RECT  788.495 601.27 789.295 602.07 ;
    END
  END rsp_data[48]
  PIN rsp_data[49]
    DIRECTION OUTPUT ;
    USE SIGNAL ;
    PORT
      LAYER metal10 ;
        RECT  791.695 601.27 792.495 602.07 ;
    END
  END rsp_data[49]
  PIN rsp_data[4]
    DIRECTION OUTPUT ;
    USE SIGNAL ;
    PORT
      LAYER metal10 ;
        RECT  801.295 588.47 802.095 589.27 ;
    END
  END rsp_data[4]
  PIN rsp_data[50]
    DIRECTION OUTPUT ;
    USE SIGNAL ;
    PORT
      LAYER metal10 ;
        RECT  794.895 601.27 795.695 602.07 ;
    END
  END rsp_data[50]
  PIN rsp_data[51]
    DIRECTION OUTPUT ;
    USE SIGNAL ;
    PORT
      LAYER metal10 ;
        RECT  798.095 601.27 798.895 602.07 ;
    END
  END rsp_data[51]
  PIN rsp_data[52]
    DIRECTION OUTPUT ;
    USE SIGNAL ;
    PORT
      LAYER metal10 ;
        RECT  801.295 601.27 802.095 602.07 ;
    END
  END rsp_data[52]
  PIN rsp_data[53]
    DIRECTION OUTPUT ;
    USE SIGNAL ;
    PORT
      LAYER metal10 ;
        RECT  804.495 601.27 805.295 602.07 ;
    END
  END rsp_data[53]
  PIN rsp_data[54]
    DIRECTION OUTPUT ;
    USE SIGNAL ;
    PORT
      LAYER metal10 ;
        RECT  807.695 601.27 808.495 602.07 ;
    END
  END rsp_data[54]
  PIN rsp_data[55]
    DIRECTION OUTPUT ;
    USE SIGNAL ;
    PORT
      LAYER metal10 ;
        RECT  810.895 601.27 811.695 602.07 ;
    END
  END rsp_data[55]
  PIN rsp_data[56]
    DIRECTION OUTPUT ;
    USE SIGNAL ;
    PORT
      LAYER metal10 ;
        RECT  814.095 601.27 814.895 602.07 ;
    END
  END rsp_data[56]
  PIN rsp_data[57]
    DIRECTION OUTPUT ;
    USE SIGNAL ;
    PORT
      LAYER metal10 ;
        RECT  817.295 601.27 818.095 602.07 ;
    END
  END rsp_data[57]
  PIN rsp_data[58]
    DIRECTION OUTPUT ;
    USE SIGNAL ;
    PORT
      LAYER metal10 ;
        RECT  820.495 601.27 821.295 602.07 ;
    END
  END rsp_data[58]
  PIN rsp_data[59]
    DIRECTION OUTPUT ;
    USE SIGNAL ;
    PORT
      LAYER metal10 ;
        RECT  823.695 601.27 824.495 602.07 ;
    END
  END rsp_data[59]
  PIN rsp_data[5]
    DIRECTION OUTPUT ;
    USE SIGNAL ;
    PORT
      LAYER metal10 ;
        RECT  804.495 588.47 805.295 589.27 ;
    END
  END rsp_data[5]
  PIN rsp_data[60]
    DIRECTION OUTPUT ;
    USE SIGNAL ;
    PORT
      LAYER metal10 ;
        RECT  788.495 604.47 789.295 605.27 ;
    END
  END rsp_data[60]
  PIN rsp_data[61]
    DIRECTION OUTPUT ;
    USE SIGNAL ;
    PORT
      LAYER metal10 ;
        RECT  791.695 604.47 792.495 605.27 ;
    END
  END rsp_data[61]
  PIN rsp_data[62]
    DIRECTION OUTPUT ;
    USE SIGNAL ;
    PORT
      LAYER metal10 ;
        RECT  794.895 604.47 795.695 605.27 ;
    END
  END rsp_data[62]
  PIN rsp_data[63]
    DIRECTION OUTPUT ;
    USE SIGNAL ;
    PORT
      LAYER metal10 ;
        RECT  798.095 604.47 798.895 605.27 ;
    END
  END rsp_data[63]
  PIN rsp_data[64]
    DIRECTION OUTPUT ;
    USE SIGNAL ;
    PORT
      LAYER metal10 ;
        RECT  801.295 604.47 802.095 605.27 ;
    END
  END rsp_data[64]
  PIN rsp_data[65]
    DIRECTION OUTPUT ;
    USE SIGNAL ;
    PORT
      LAYER metal10 ;
        RECT  804.495 604.47 805.295 605.27 ;
    END
  END rsp_data[65]
  PIN rsp_data[66]
    DIRECTION OUTPUT ;
    USE SIGNAL ;
    PORT
      LAYER metal10 ;
        RECT  807.695 604.47 808.495 605.27 ;
    END
  END rsp_data[66]
  PIN rsp_data[67]
    DIRECTION OUTPUT ;
    USE SIGNAL ;
    PORT
      LAYER metal10 ;
        RECT  810.895 604.47 811.695 605.27 ;
    END
  END rsp_data[67]
  PIN rsp_data[68]
    DIRECTION OUTPUT ;
    USE SIGNAL ;
    PORT
      LAYER metal10 ;
        RECT  814.095 604.47 814.895 605.27 ;
    END
  END rsp_data[68]
  PIN rsp_data[69]
    DIRECTION OUTPUT ;
    USE SIGNAL ;
    PORT
      LAYER metal10 ;
        RECT  817.295 604.47 818.095 605.27 ;
    END
  END rsp_data[69]
  PIN rsp_data[6]
    DIRECTION OUTPUT ;
    USE SIGNAL ;
    PORT
      LAYER metal10 ;
        RECT  807.695 588.47 808.495 589.27 ;
    END
  END rsp_data[6]
  PIN rsp_data[70]
    DIRECTION OUTPUT ;
    USE SIGNAL ;
    PORT
      LAYER metal10 ;
        RECT  820.495 604.47 821.295 605.27 ;
    END
  END rsp_data[70]
  PIN rsp_data[71]
    DIRECTION OUTPUT ;
    USE SIGNAL ;
    PORT
      LAYER metal10 ;
        RECT  823.695 604.47 824.495 605.27 ;
    END
  END rsp_data[71]
  PIN rsp_data[72]
    DIRECTION OUTPUT ;
    USE SIGNAL ;
    PORT
      LAYER metal10 ;
        RECT  788.495 607.67 789.295 608.47 ;
    END
  END rsp_data[72]
  PIN rsp_data[73]
    DIRECTION OUTPUT ;
    USE SIGNAL ;
    PORT
      LAYER metal10 ;
        RECT  791.695 607.67 792.495 608.47 ;
    END
  END rsp_data[73]
  PIN rsp_data[74]
    DIRECTION OUTPUT ;
    USE SIGNAL ;
    PORT
      LAYER metal10 ;
        RECT  794.895 607.67 795.695 608.47 ;
    END
  END rsp_data[74]
  PIN rsp_data[75]
    DIRECTION OUTPUT ;
    USE SIGNAL ;
    PORT
      LAYER metal10 ;
        RECT  798.095 607.67 798.895 608.47 ;
    END
  END rsp_data[75]
  PIN rsp_data[76]
    DIRECTION OUTPUT ;
    USE SIGNAL ;
    PORT
      LAYER metal10 ;
        RECT  801.295 607.67 802.095 608.47 ;
    END
  END rsp_data[76]
  PIN rsp_data[77]
    DIRECTION OUTPUT ;
    USE SIGNAL ;
    PORT
      LAYER metal10 ;
        RECT  804.495 607.67 805.295 608.47 ;
    END
  END rsp_data[77]
  PIN rsp_data[78]
    DIRECTION OUTPUT ;
    USE SIGNAL ;
    PORT
      LAYER metal10 ;
        RECT  807.695 607.67 808.495 608.47 ;
    END
  END rsp_data[78]
  PIN rsp_data[79]
    DIRECTION OUTPUT ;
    USE SIGNAL ;
    PORT
      LAYER metal10 ;
        RECT  810.895 607.67 811.695 608.47 ;
    END
  END rsp_data[79]
  PIN rsp_data[7]
    DIRECTION OUTPUT ;
    USE SIGNAL ;
    PORT
      LAYER metal10 ;
        RECT  810.895 588.47 811.695 589.27 ;
    END
  END rsp_data[7]
  PIN rsp_data[80]
    DIRECTION OUTPUT ;
    USE SIGNAL ;
    PORT
      LAYER metal10 ;
        RECT  814.095 607.67 814.895 608.47 ;
    END
  END rsp_data[80]
  PIN rsp_data[81]
    DIRECTION OUTPUT ;
    USE SIGNAL ;
    PORT
      LAYER metal10 ;
        RECT  817.295 607.67 818.095 608.47 ;
    END
  END rsp_data[81]
  PIN rsp_data[82]
    DIRECTION OUTPUT ;
    USE SIGNAL ;
    PORT
      LAYER metal10 ;
        RECT  820.495 607.67 821.295 608.47 ;
    END
  END rsp_data[82]
  PIN rsp_data[83]
    DIRECTION OUTPUT ;
    USE SIGNAL ;
    PORT
      LAYER metal10 ;
        RECT  823.695 607.67 824.495 608.47 ;
    END
  END rsp_data[83]
  PIN rsp_data[84]
    DIRECTION OUTPUT ;
    USE SIGNAL ;
    PORT
      LAYER metal10 ;
        RECT  788.495 610.87 789.295 611.67 ;
    END
  END rsp_data[84]
  PIN rsp_data[85]
    DIRECTION OUTPUT ;
    USE SIGNAL ;
    PORT
      LAYER metal10 ;
        RECT  791.695 610.87 792.495 611.67 ;
    END
  END rsp_data[85]
  PIN rsp_data[86]
    DIRECTION OUTPUT ;
    USE SIGNAL ;
    PORT
      LAYER metal10 ;
        RECT  794.895 610.87 795.695 611.67 ;
    END
  END rsp_data[86]
  PIN rsp_data[87]
    DIRECTION OUTPUT ;
    USE SIGNAL ;
    PORT
      LAYER metal10 ;
        RECT  798.095 610.87 798.895 611.67 ;
    END
  END rsp_data[87]
  PIN rsp_data[88]
    DIRECTION OUTPUT ;
    USE SIGNAL ;
    PORT
      LAYER metal10 ;
        RECT  801.295 610.87 802.095 611.67 ;
    END
  END rsp_data[88]
  PIN rsp_data[89]
    DIRECTION OUTPUT ;
    USE SIGNAL ;
    PORT
      LAYER metal10 ;
        RECT  804.495 610.87 805.295 611.67 ;
    END
  END rsp_data[89]
  PIN rsp_data[8]
    DIRECTION OUTPUT ;
    USE SIGNAL ;
    PORT
      LAYER metal10 ;
        RECT  814.095 588.47 814.895 589.27 ;
    END
  END rsp_data[8]
  PIN rsp_data[90]
    DIRECTION OUTPUT ;
    USE SIGNAL ;
    PORT
      LAYER metal10 ;
        RECT  807.695 610.87 808.495 611.67 ;
    END
  END rsp_data[90]
  PIN rsp_data[91]
    DIRECTION OUTPUT ;
    USE SIGNAL ;
    PORT
      LAYER metal10 ;
        RECT  810.895 610.87 811.695 611.67 ;
    END
  END rsp_data[91]
  PIN rsp_data[92]
    DIRECTION OUTPUT ;
    USE SIGNAL ;
    PORT
      LAYER metal10 ;
        RECT  814.095 610.87 814.895 611.67 ;
    END
  END rsp_data[92]
  PIN rsp_data[93]
    DIRECTION OUTPUT ;
    USE SIGNAL ;
    PORT
      LAYER metal10 ;
        RECT  817.295 610.87 818.095 611.67 ;
    END
  END rsp_data[93]
  PIN rsp_data[94]
    DIRECTION OUTPUT ;
    USE SIGNAL ;
    PORT
      LAYER metal10 ;
        RECT  820.495 610.87 821.295 611.67 ;
    END
  END rsp_data[94]
  PIN rsp_data[95]
    DIRECTION OUTPUT ;
    USE SIGNAL ;
    PORT
      LAYER metal10 ;
        RECT  823.695 610.87 824.495 611.67 ;
    END
  END rsp_data[95]
  PIN rsp_data[96]
    DIRECTION OUTPUT ;
    USE SIGNAL ;
    PORT
      LAYER metal10 ;
        RECT  788.495 614.07 789.295 614.87 ;
    END
  END rsp_data[96]
  PIN rsp_data[97]
    DIRECTION OUTPUT ;
    USE SIGNAL ;
    PORT
      LAYER metal10 ;
        RECT  791.695 614.07 792.495 614.87 ;
    END
  END rsp_data[97]
  PIN rsp_data[98]
    DIRECTION OUTPUT ;
    USE SIGNAL ;
    PORT
      LAYER metal10 ;
        RECT  794.895 614.07 795.695 614.87 ;
    END
  END rsp_data[98]
  PIN rsp_data[99]
    DIRECTION OUTPUT ;
    USE SIGNAL ;
    PORT
      LAYER metal10 ;
        RECT  798.095 614.07 798.895 614.87 ;
    END
  END rsp_data[99]
  PIN rsp_data[9]
    DIRECTION OUTPUT ;
    USE SIGNAL ;
    PORT
      LAYER metal10 ;
        RECT  817.295 588.47 818.095 589.27 ;
    END
  END rsp_data[9]
  PIN rsp_error
    DIRECTION OUTPUT ;
    USE SIGNAL ;
    PORT
      LAYER metal10 ;
        RECT  1.295 74.87 2.095 75.67 ;
    END
  END rsp_error
  PIN rsp_ready
    DIRECTION INPUT ;
    USE SIGNAL ;
    PORT
      LAYER metal10 ;
        RECT  1.295 78.07 2.095 78.87 ;
    END
  END rsp_ready
  PIN rsp_saturated
    DIRECTION OUTPUT ;
    USE SIGNAL ;
    PORT
      LAYER metal10 ;
        RECT  1.295 81.27 2.095 82.07 ;
    END
  END rsp_saturated
  PIN rsp_valid
    DIRECTION OUTPUT ;
    USE SIGNAL ;
    PORT
      LAYER metal10 ;
        RECT  1.295 84.47 2.095 85.27 ;
    END
  END rsp_valid
  PIN VSS
    DIRECTION INOUT ;
    USE GROUND ;
    PORT
      LAYER metal7 ;
        RECT  20.14 1162.3 1189.97 1163.7 ;
        RECT  20.14 1132.3 1189.97 1133.7 ;
        RECT  20.14 1102.3 1189.97 1103.7 ;
        RECT  20.14 1072.3 1189.97 1073.7 ;
        RECT  20.14 1042.3 1189.97 1043.7 ;
        RECT  20.14 1012.3 1189.97 1013.7 ;
        RECT  20.14 982.3 1189.97 983.7 ;
        RECT  20.14 952.3 1189.97 953.7 ;
        RECT  20.14 922.3 1189.97 923.7 ;
        RECT  20.14 892.3 1189.97 893.7 ;
        RECT  20.14 862.3 1189.97 863.7 ;
        RECT  20.14 832.3 1189.97 833.7 ;
        RECT  20.14 802.3 1189.97 803.7 ;
        RECT  20.14 772.3 1189.97 773.7 ;
        RECT  20.14 742.3 1189.97 743.7 ;
        RECT  20.14 712.3 1189.97 713.7 ;
        RECT  20.14 682.3 1189.97 683.7 ;
        RECT  20.14 652.3 1189.97 653.7 ;
        RECT  20.14 622.3 1189.97 623.7 ;
        RECT  20.14 592.3 1189.97 593.7 ;
        RECT  20.14 562.3 1189.97 563.7 ;
        RECT  20.14 532.3 1189.97 533.7 ;
        RECT  20.14 502.3 1189.97 503.7 ;
        RECT  20.14 472.3 1189.97 473.7 ;
        RECT  20.14 442.3 1189.97 443.7 ;
        RECT  20.14 412.3 1189.97 413.7 ;
        RECT  20.14 382.3 1189.97 383.7 ;
        RECT  20.14 352.3 1189.97 353.7 ;
        RECT  20.14 322.3 1189.97 323.7 ;
        RECT  20.14 292.3 1189.97 293.7 ;
        RECT  20.14 262.3 1189.97 263.7 ;
        RECT  20.14 232.3 1189.97 233.7 ;
        RECT  20.14 202.3 1189.97 203.7 ;
        RECT  20.14 172.3 1189.97 173.7 ;
        RECT  20.14 142.3 1189.97 143.7 ;
        RECT  20.14 112.3 1189.97 113.7 ;
        RECT  20.14 82.3 1189.97 83.7 ;
        RECT  20.14 52.3 1189.97 53.7 ;
        RECT  20.14 22.3 1189.97 23.7 ;
    END
  END VSS
  PIN VDD
    DIRECTION INOUT ;
    USE POWER ;
    PORT
      LAYER metal7 ;
        RECT  20.14 1177.3 1189.97 1178.7 ;
        RECT  20.14 1147.3 1189.97 1148.7 ;
        RECT  20.14 1117.3 1189.97 1118.7 ;
        RECT  20.14 1087.3 1189.97 1088.7 ;
        RECT  20.14 1057.3 1189.97 1058.7 ;
        RECT  20.14 1027.3 1189.97 1028.7 ;
        RECT  20.14 997.3 1189.97 998.7 ;
        RECT  20.14 967.3 1189.97 968.7 ;
        RECT  20.14 937.3 1189.97 938.7 ;
        RECT  20.14 907.3 1189.97 908.7 ;
        RECT  20.14 877.3 1189.97 878.7 ;
        RECT  20.14 847.3 1189.97 848.7 ;
        RECT  20.14 817.3 1189.97 818.7 ;
        RECT  20.14 787.3 1189.97 788.7 ;
        RECT  20.14 757.3 1189.97 758.7 ;
        RECT  20.14 727.3 1189.97 728.7 ;
        RECT  20.14 697.3 1189.97 698.7 ;
        RECT  20.14 667.3 1189.97 668.7 ;
        RECT  20.14 637.3 1189.97 638.7 ;
        RECT  20.14 607.3 1189.97 608.7 ;
        RECT  20.14 577.3 1189.97 578.7 ;
        RECT  20.14 547.3 1189.97 548.7 ;
        RECT  20.14 517.3 1189.97 518.7 ;
        RECT  20.14 487.3 1189.97 488.7 ;
        RECT  20.14 457.3 1189.97 458.7 ;
        RECT  20.14 427.3 1189.97 428.7 ;
        RECT  20.14 397.3 1189.97 398.7 ;
        RECT  20.14 367.3 1189.97 368.7 ;
        RECT  20.14 337.3 1189.97 338.7 ;
        RECT  20.14 307.3 1189.97 308.7 ;
        RECT  20.14 277.3 1189.97 278.7 ;
        RECT  20.14 247.3 1189.97 248.7 ;
        RECT  20.14 217.3 1189.97 218.7 ;
        RECT  20.14 187.3 1189.97 188.7 ;
        RECT  20.14 157.3 1189.97 158.7 ;
        RECT  20.14 127.3 1189.97 128.7 ;
        RECT  20.14 97.3 1189.97 98.7 ;
        RECT  20.14 67.3 1189.97 68.7 ;
        RECT  20.14 37.3 1189.97 38.7 ;
    END
  END VDD
  OBS
    LAYER metal1 ;
     RECT  0.495 18.87 1206.665 1209.87 ;
    LAYER metal2 ;
     RECT  0.495 18.87 1206.665 1209.87 ;
    LAYER metal3 ;
     RECT  0.495 18.87 1206.665 1209.87 ;
    LAYER metal4 ;
     RECT  0.495 18.87 1206.665 1209.87 ;
    LAYER metal5 ;
     RECT  0.495 18.87 1206.665 1209.87 ;
    LAYER metal6 ;
     RECT  0.495 18.87 1206.665 1209.87 ;
    LAYER metal7 ;
     RECT  0.495 18.87 1206.665 1209.87 ;
    LAYER metal8 ;
     RECT  0.495 18.87 1206.665 1209.87 ;
    LAYER metal9 ;
     RECT  0.495 18.87 1206.665 1209.87 ;
    LAYER metal10 ;
     RECT  0.495 18.87 1206.665 1209.87 ;
  END
END block_v1_v
END LIBRARY
